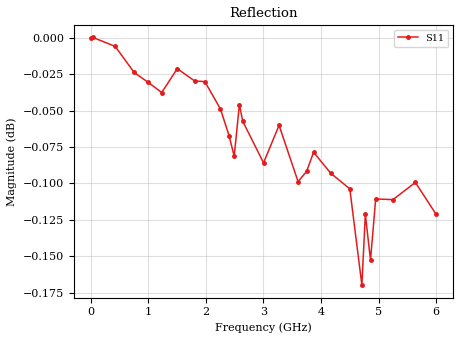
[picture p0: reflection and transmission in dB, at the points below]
! NMT Kit SMA(f) typ SOLT V1 - Open s1p data
! Ref Plane 0 mm
#  MHz  S  RI  R  50
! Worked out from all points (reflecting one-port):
!   201 points, 1 MHz to 6.001 GHz, reference 50 ohm
!   lowest |S11| = -0.2 dB at 4.711 GHz (marker M1), VSWR 102.22, Z = 0.49 - j1.88 ohm
!   phase of S11 starts at 0 deg and turns -223 deg over the sweep
!   S11 on the Smith chart (normalised r, x): 1 MHz: open; 1.231 GHz: 0.01, -2.37; 2.401 GHz: 0.01, -1.00; 3.601 GHz: 0.01, -0.42; 4.771 GHz: 0.01, -0.02; 6.001 GHz: 0.01, +0.39
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1  1 0.0014
31  1 -0.00541
421  0.9654 -0.2581
751  0.8872 -0.4554
991  0.7995 -0.5948
1231  0.6958 -0.7122
1501  0.5624 -0.8239
1801  0.386 -0.9188
1981  0.2765 -0.9574
2251  0.1024 -0.9891
2401  0.00121 -0.9923
2491  -0.0462 -0.9896
2581  -0.1162 -0.9879
2641  -0.1434 -0.983
3001  -0.3733 -0.9171
3271  -0.5277 -0.8413
3601  -0.6941 -0.7041
3751  -0.7582 -0.6358
3871  -0.8108 -0.5698
4171  -0.9031 -0.404
4501  -0.9676 -0.2004
4711  -0.9779 -0.0735
4771  -0.9857 -0.0298
4861  -0.9824 0.0197
4951  -0.9835 0.0871
5251  -0.9498 0.2695
5641  -0.8598 0.488
6001  -0.7224 0.6713
